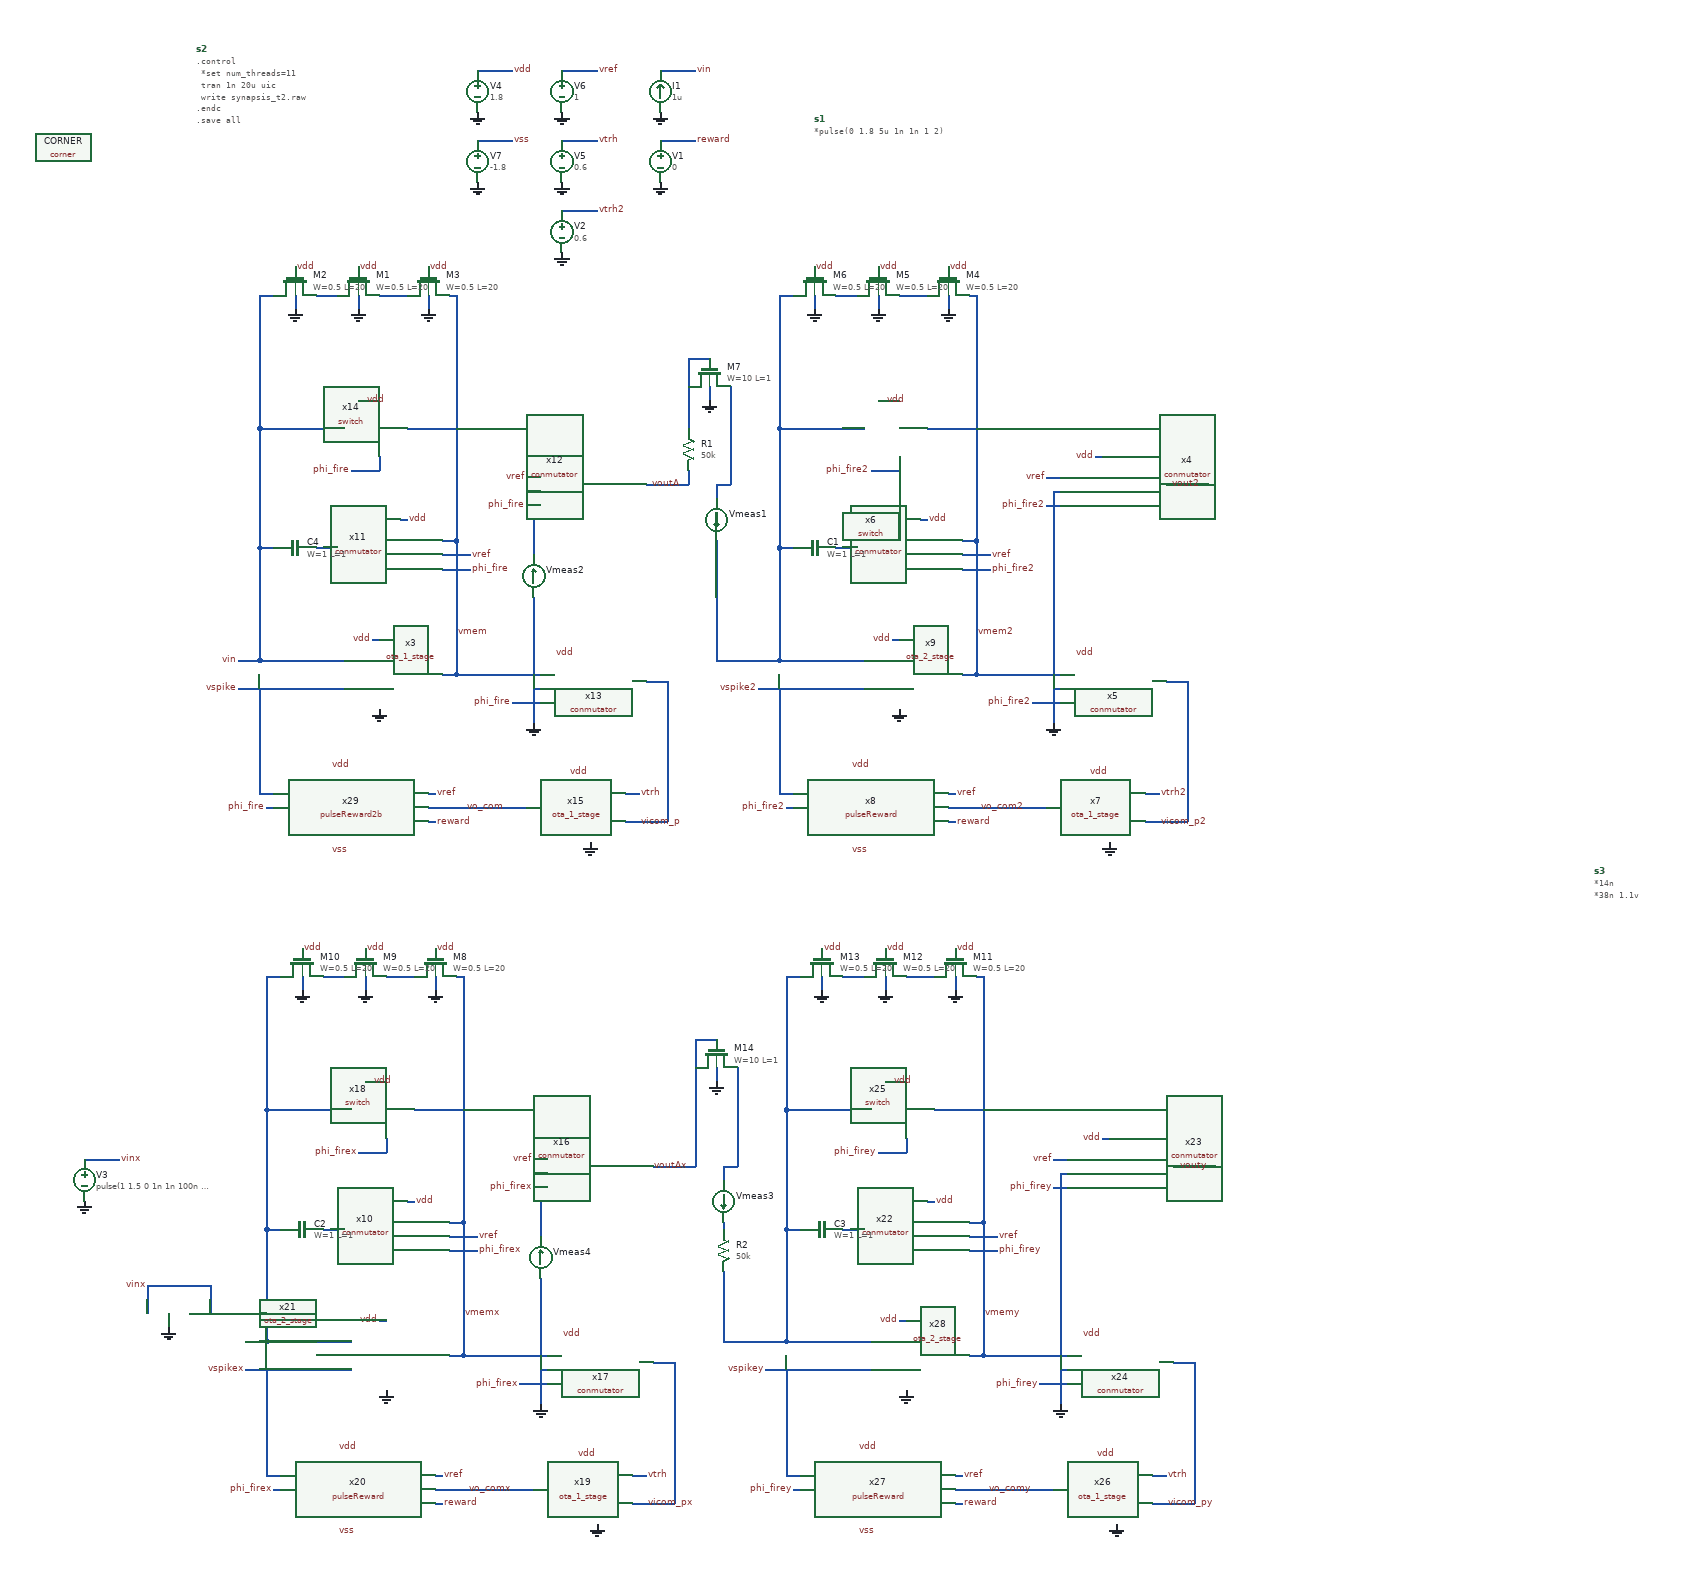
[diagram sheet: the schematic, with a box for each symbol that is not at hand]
v {xschem version=3.4.7 file_version=1.2}
G {}
K {}
V {}
S {}
E {}
B 2 1620 -1070 2420 -670 {flags=graph
y1=0.55
y2=1.3
ypos1=0
ypos2=2
divy=5
subdivy=1
unity=1
x1=9.6886622e-06
x2=1.1063051e-05
divx=5
subdivx=1
xlabmag=1.0
ylabmag=1.0
node="vmem
vtrh"
color="5 9"
dataset=-1
unitx=1
logx=0
logy=0
}
B 2 1620 -670 2420 -270 {flags=graph
y1=0.58
y2=1.7
ypos1=0
ypos2=2
divy=5
subdivy=1
unity=1
x1=9.6886622e-06
x2=1.1063051e-05
divx=5
subdivx=1
xlabmag=1.0
ylabmag=1.0
node="vmem2
vtrh"
color="7 9"
dataset=-1
unitx=1
logx=0
logy=0
}
B 2 2420 -1070 3220 -670 {flags=graph
y1=0.82
y2=1.3
ypos1=0
ypos2=2
divy=5
subdivy=1
unity=1
x1=9.6886622e-06
x2=1.1063051e-05
divx=5
subdivx=1
xlabmag=1.0
ylabmag=1.0
node=vouta
color=4
dataset=-1
unitx=1
logx=0
logy=0
}
B 2 2420 -670 3220 -270 {flags=graph
y1=0.58
y2=1.7
ypos1=0
ypos2=2
divy=5
subdivy=1
unity=1
x1=9.6886622e-06
x2=1.1063051e-05
divx=5
subdivx=1
xlabmag=1.0
ylabmag=1.0
node=vout2
color=4
dataset=-1
unitx=1
logx=0
logy=0
}
B 2 1890 -1530 2690 -1130 {flags=graph
y1=-10e-06
y2=10e-6
ypos1=0
ypos2=2
divy=5
subdivy=1
unity=1
x1=9.6886622e-06
x2=1.1063051e-05
divx=5
subdivx=1
xlabmag=1.0
ylabmag=1.0
node="I(Vmeas1)
I(Vmeas2)"
color="4 5"
dataset=-1
unitx=1
logx=0
logy=0
}
B 2 2690 -1530 3490 -1130 {flags=graph
y1=-1.8e-05
y2=1.1e-05
ypos1=0
ypos2=2
divy=5
subdivy=1
unity=1
x1=9.6886622e-06
x2=1.1063051e-05
divx=5
subdivx=1
xlabmag=1.0
ylabmag=1.0
node="I(Vmeas1)
I(Vmeas2)"
color=4
dataset=-1
unitx=1
logx=0
logy=0
}
B 2 1660 -40 2460 360 {flags=graph
y1=-0.04
y2=1.8
ypos1=0
ypos2=2
divy=5
subdivy=1
unity=1
x1=9.6886622e-06
x2=1.1063051e-05
divx=5
subdivx=1
xlabmag=1.0
ylabmag=1.0
node="vmemx
vtrh"
color="5 9"
dataset=-1
unitx=1
logx=0
logy=0
}
B 2 1660 360 2460 760 {flags=graph
y1=0.59
y2=1.7
ypos1=0
ypos2=2
divy=5
subdivy=1
unity=1
x1=9.6886622e-06
x2=1.1063051e-05
divx=5
subdivx=1
xlabmag=1.0
ylabmag=1.0
node="vmemy
vtrh"
color="7 9"
dataset=-1
unitx=1
logx=0
logy=0
}
B 2 2460 -40 3260 360 {flags=graph
y1=0.024
y2=1.8
ypos1=0
ypos2=2
divy=5
subdivy=1
unity=1
x1=9.6886622e-06
x2=1.1063051e-05
divx=5
subdivx=1
xlabmag=1.0
ylabmag=1.0
node="voutAx
vinx"
color="4 8"
dataset=-1
unitx=1
logx=0
logy=0
}
B 2 2460 360 3260 760 {flags=graph
y1=0.59
y2=1.7
ypos1=0
ypos2=2
divy=5
subdivy=1
unity=1
x1=9.6886622e-06
x2=1.1063051e-05
divx=5
subdivx=1
xlabmag=1.0
ylabmag=1.0
node=vouty
color=4
dataset=-1
unitx=1
logx=0
logy=0
}
N 460 -1340 510 -1340 {
lab=vdd}
N 720 -1340 770 -1340 {
lab=vin}
N 580 -1240 630 -1240 {
lab=vtrh}
N 580 -1340 630 -1340 {
lab=vref}
N 460 -1240 510 -1240 {
lab=vss}
N 720 -1240 770 -1240 {
lab=reward}
N 500 -290 530 -290 {
lab=vo_com}
N 530 -720 550 -720 {
lab=phi_fire}
N 530 -760 550 -760 {
lab=vref}
N 700 -750 720 -750 {
lab=voutA}
N 310 -530 320 -530 {
lab=vdd}
N 350 -700 360 -700 {
lab=vdd}
N 410 -650 450 -650 {
lab=vref}
N 410 -670 430 -670 {
lab=vmem}
N 410 -630 450 -630 {
lab=phi_fire}
N 230 -660 260 -660 {
lab=#net1}
N 430 -940 430 -670 {
lab=vmem}
N 150 -830 150 -660 {
lab=vin}
N 150 -660 170 -660 {
lab=vin}
N 150 -940 150 -830 {
lab=vin}
N 320 -790 320 -770 {
lab=phi_fire}
N 280 -770 320 -770 {
lab=phi_fire}
N 430 -670 430 -480 {
lab=vmem}
N 150 -660 150 -500 {
lab=vin}
N 150 -500 270 -500 {
lab=vin}
N 120 -500 150 -500 {
lab=vin}
N 530 -440 550 -440 {
lab=phi_fire}
N 360 -830 430 -830 {
lab=vmem}
N 150 -830 270 -830 {
lab=vin}
N 290 -870 300 -870 {
lab=vdd}
N 720 -750 760 -750 {
lab=voutA}
N 410 -480 430 -480 {
lab=vmem}
N 600 -790 610 -790 {
lab=vdd}
N 120 -460 270 -460 {
lab=vspike}
N 150 -460 150 -360 {
lab=vspike}
N 390 -290 500 -290 {
lab=vo_com}
N 390 -310 400 -310 {
lab=vref}
N 160 -290 170 -290 {
lab=phi_fire}
N 150 -980 150 -940 {
lab=vin}
N 430 -980 430 -940 {
lab=vmem}
N 390 -270 400 -270 {
lab=reward}
N 150 -310 170 -310 {
lab=vspike}
N 150 -360 150 -310 {
lab=vspike}
N 540 -740 550 -740 {
lab=#net2}
N 670 -310 690 -310 {
lab=vtrh}
N 700 -470 720 -470 {
lab=vicom_p}
N 730 -470 730 -270 {
lab=vicom_p}
N 720 -470 730 -470 {
lab=vicom_p}
N 670 -270 730 -270 {
lab=vicom_p}
N 430 -480 550 -480 {
lab=vmem}
N 510 -440 530 -440 {
lab=phi_fire}
N 540 -460 540 -410 {
lab=GND}
N 540 -460 550 -460 {
lab=GND}
N 390 -1020 390 -1000 {
lab=GND}
N 150 -1020 150 -980 {
lab=vin}
N 430 -1020 430 -980 {
lab=vmem}
N 290 -1020 290 -1000 {
lab=GND}
N 200 -1020 200 -1000 {
lab=GND}
N 150 -1020 170 -1020 {lab=vin}
N 230 -1020 260 -1020 {lab=#net3}
N 320 -1020 360 -1020 {lab=#net4}
N 420 -1020 430 -1020 {lab=vmem}
N 1240 -290 1270 -290 {
lab=vo_com2}
N 1270 -720 1290 -720 {
lab=phi_fire2}
N 1270 -760 1290 -760 {
lab=vref}
N 1440 -750 1460 -750 {
lab=vout2}
N 1050 -530 1060 -530 {
lab=vdd}
N 1090 -700 1100 -700 {
lab=vdd}
N 1150 -650 1190 -650 {
lab=vref}
N 1150 -670 1170 -670 {
lab=vmem2}
N 1150 -630 1190 -630 {
lab=phi_fire2}
N 970 -660 1000 -660 {
lab=#net5}
N 1170 -940 1170 -670 {
lab=vmem2}
N 890 -830 890 -660 {
lab=#net6}
N 890 -660 910 -660 {
lab=#net6}
N 890 -940 890 -830 {
lab=#net6}
N 1060 -790 1060 -770 {
lab=phi_fire2}
N 1020 -770 1060 -770 {
lab=phi_fire2}
N 1170 -670 1170 -480 {
lab=vmem2}
N 890 -660 890 -500 {
lab=#net6}
N 890 -500 1010 -500 {
lab=#net6}
N 860 -500 890 -500 {
lab=#net6}
N 1270 -440 1290 -440 {
lab=phi_fire2}
N 1100 -830 1170 -830 {
lab=vmem2}
N 890 -830 1010 -830 {
lab=#net6}
N 1030 -870 1040 -870 {
lab=vdd}
N 1460 -750 1500 -750 {
lab=vout2}
N 1150 -480 1170 -480 {
lab=vmem2}
N 1340 -790 1350 -790 {
lab=vdd}
N 860 -460 1010 -460 {
lab=vspike2}
N 890 -460 890 -360 {
lab=vspike2}
N 1130 -290 1240 -290 {
lab=vo_com2}
N 1130 -310 1140 -310 {
lab=vref}
N 900 -290 910 -290 {
lab=phi_fire2}
N 890 -980 890 -940 {
lab=#net6}
N 1170 -980 1170 -940 {
lab=vmem2}
N 1130 -270 1140 -270 {
lab=reward}
N 890 -310 910 -310 {
lab=vspike2}
N 890 -360 890 -310 {
lab=vspike2}
N 1280 -740 1290 -740 {
lab=vmem2}
N 1280 -740 1280 -480 {
lab=vmem2}
N 1410 -310 1430 -310 {
lab=vtrh2}
N 1440 -470 1460 -470 {
lab=vicom_p2}
N 1470 -470 1470 -270 {
lab=vicom_p2}
N 1460 -470 1470 -470 {
lab=vicom_p2}
N 1410 -270 1470 -270 {
lab=vicom_p2}
N 1170 -480 1290 -480 {
lab=vmem2}
N 1250 -440 1270 -440 {
lab=phi_fire2}
N 1280 -460 1280 -410 {
lab=GND}
N 1280 -460 1290 -460 {
lab=GND}
N 1130 -1020 1130 -1000 {
lab=GND}
N 890 -1020 890 -980 {
lab=#net6}
N 1170 -1020 1170 -980 {
lab=vmem2}
N 1030 -1020 1030 -1000 {
lab=GND}
N 940 -1020 940 -1000 {
lab=GND}
N 890 -1020 910 -1020 {lab=#net6}
N 970 -1020 1000 -1020 {lab=#net7}
N 1060 -1020 1100 -1020 {lab=#net8}
N 1160 -1020 1170 -1020 {lab=vmem2}
N 800 -500 860 -500 {lab=#net6}
N 580 -1140 630 -1140 {
lab=vtrh2}
N 800 -600 800 -500 {lab=#net6}
N 800 -670 800 -660 {lab=#net6}
N 800 -750 800 -730 {lab=#net9}
N 760 -770 760 -750 {lab=voutA}
N 530 -740 540 -740 {lab=#net2}
N 540 -740 540 -650 {lab=#net2}
N 540 -590 540 -480 {lab=vmem}
N 760 -930 760 -890 {lab=#net10}
N 760 -930 790 -930 {lab=#net10}
N 790 -890 790 -870 {lab=GND}
N 820 -890 820 -750 {lab=#net9}
N 800 -750 820 -750 {lab=#net9}
N 510 680 540 680 {
lab=vo_comx}
N 540 250 560 250 {
lab=phi_firex}
N 540 210 560 210 {
lab=vref}
N 710 220 730 220 {
lab=voutAx}
N 320 440 330 440 {
lab=vdd}
N 360 270 370 270 {
lab=vdd}
N 420 320 460 320 {
lab=vref}
N 420 300 440 300 {
lab=vmemx}
N 420 340 460 340 {
lab=phi_firex}
N 240 310 270 310 {
lab=#net11}
N 440 30 440 300 {
lab=vmemx}
N 160 140 160 310 {
lab=vinx}
N 160 310 180 310 {
lab=vinx}
N 160 30 160 140 {
lab=vinx}
N 330 180 330 200 {
lab=phi_firex}
N 290 200 330 200 {
lab=phi_firex}
N 440 300 440 490 {
lab=vmemx}
N 160 310 160 470 {
lab=vinx}
N 160 470 280 470 {
lab=vinx}
N 130 470 160 470 {
lab=vinx}
N 540 530 560 530 {
lab=phi_firex}
N 370 140 440 140 {
lab=vmemx}
N 160 140 280 140 {
lab=vinx}
N 300 100 310 100 {
lab=vdd}
N 730 220 770 220 {
lab=voutAx}
N 420 490 440 490 {
lab=vmemx}
N 610 180 620 180 {
lab=vdd}
N 130 510 280 510 {
lab=vspikex}
N 160 510 160 610 {
lab=vspikex}
N 400 680 510 680 {
lab=vo_comx}
N 400 660 410 660 {
lab=vref}
N 170 680 180 680 {
lab=phi_firex}
N 160 -10 160 30 {
lab=vinx}
N 440 -10 440 30 {
lab=vmemx}
N 400 700 410 700 {
lab=reward}
N 160 660 180 660 {
lab=vspikex}
N 160 610 160 660 {
lab=vspikex}
N 550 230 560 230 {
lab=#net12}
N 680 660 700 660 {
lab=vtrh}
N 710 500 730 500 {
lab=vicom_px}
N 740 500 740 700 {
lab=vicom_px}
N 730 500 740 500 {
lab=vicom_px}
N 680 700 740 700 {
lab=vicom_px}
N 440 490 560 490 {
lab=vmemx}
N 520 530 540 530 {
lab=phi_firex}
N 550 510 550 560 {
lab=GND}
N 550 510 560 510 {
lab=GND}
N 400 -50 400 -30 {
lab=GND}
N 160 -50 160 -10 {
lab=vinx}
N 440 -50 440 -10 {
lab=vmemx}
N 300 -50 300 -30 {
lab=GND}
N 210 -50 210 -30 {
lab=GND}
N 160 -50 180 -50 {lab=vinx}
N 240 -50 270 -50 {lab=#net13}
N 330 -50 370 -50 {lab=#net14}
N 430 -50 440 -50 {lab=vmemx}
N 1250 680 1280 680 {
lab=vo_comy}
N 1280 250 1300 250 {
lab=phi_firey}
N 1280 210 1300 210 {
lab=vref}
N 1450 220 1470 220 {
lab=vouty}
N 1060 440 1070 440 {
lab=vdd}
N 1100 270 1110 270 {
lab=vdd}
N 1160 320 1200 320 {
lab=vref}
N 1160 300 1180 300 {
lab=vmemy}
N 1160 340 1200 340 {
lab=phi_firey}
N 980 310 1010 310 {
lab=#net15}
N 1180 30 1180 300 {
lab=vmemy}
N 900 140 900 310 {
lab=#net16}
N 900 310 920 310 {
lab=#net16}
N 900 30 900 140 {
lab=#net16}
N 1070 180 1070 200 {
lab=phi_firey}
N 1030 200 1070 200 {
lab=phi_firey}
N 1180 300 1180 490 {
lab=vmemy}
N 900 310 900 470 {
lab=#net16}
N 900 470 1020 470 {
lab=#net16}
N 870 470 900 470 {
lab=#net16}
N 1280 530 1300 530 {
lab=phi_firey}
N 1110 140 1180 140 {
lab=vmemy}
N 900 140 1020 140 {
lab=#net16}
N 1040 100 1050 100 {
lab=vdd}
N 1470 220 1510 220 {
lab=vouty}
N 1160 490 1180 490 {
lab=vmemy}
N 1350 180 1360 180 {
lab=vdd}
N 870 510 1020 510 {
lab=vspikey}
N 900 510 900 610 {
lab=vspikey}
N 1140 680 1250 680 {
lab=vo_comy}
N 1140 660 1150 660 {
lab=vref}
N 910 680 920 680 {
lab=phi_firey}
N 900 -10 900 30 {
lab=#net16}
N 1180 -10 1180 30 {
lab=vmemy}
N 1140 700 1150 700 {
lab=reward}
N 900 660 920 660 {
lab=vspikey}
N 900 610 900 660 {
lab=vspikey}
N 1290 230 1300 230 {
lab=vmemy}
N 1290 230 1290 490 {
lab=vmemy}
N 1420 660 1440 660 {
lab=vtrh}
N 1450 500 1470 500 {
lab=vicom_py}
N 1480 500 1480 700 {
lab=vicom_py}
N 1470 500 1480 500 {
lab=vicom_py}
N 1420 700 1480 700 {
lab=vicom_py}
N 1180 490 1300 490 {
lab=vmemy}
N 1260 530 1280 530 {
lab=phi_firey}
N 1290 510 1290 560 {
lab=GND}
N 1290 510 1300 510 {
lab=GND}
N 1140 -50 1140 -30 {
lab=GND}
N 900 -50 900 -10 {
lab=#net16}
N 1180 -50 1180 -10 {
lab=vmemy}
N 1040 -50 1040 -30 {
lab=GND}
N 950 -50 950 -30 {
lab=GND}
N 900 -50 920 -50 {lab=#net16}
N 980 -50 1010 -50 {lab=#net17}
N 1070 -50 1110 -50 {lab=#net18}
N 1170 -50 1180 -50 {lab=vmemy}
N 810 470 870 470 {lab=#net16}
N 810 370 810 470 {lab=#net16}
N 810 300 810 310 {lab=#net19}
N 810 220 810 240 {lab=#net20}
N 770 200 770 220 {lab=voutAx}
N 540 230 550 230 {lab=#net12}
N 550 230 550 320 {lab=#net12}
N 550 380 550 490 {lab=vmemx}
N 770 40 770 80 {lab=voutAx}
N 770 40 800 40 {lab=voutAx}
N 800 80 800 100 {lab=GND}
N 770 80 770 200 {lab=voutAx}
N 830 80 830 220 {lab=#net20}
N 810 220 830 220 {lab=#net20}
N -100 210 -50 210 {
lab=vinx}
N -10 390 -10 430 {lab=vinx}
N -10 390 20 390 {lab=vinx}
N 20 430 20 450 {lab=GND}
N 50 430 160 430 {lab=vinx}
N 760 -890 760 -830 {lab=#net10}
N 800 -660 800 -590 {lab=#net6}
N 20 390 80 390 {lab=vinx}
N 80 390 80 430 {lab=vinx}
C {devices/code_shown.sym} 60 -1370 0 0 {name=s2 only_toplevel=false value="
.control
 *set num_threads=11
 tran 1n 20u uic
 write synapsis_t2.raw
.endc
.save all" }
C {devices/gnd.sym} 720 -1280 0 0 {name=l8 lab=GND}
C {devices/vsource.sym} 460 -1310 0 0 {name=V4 value=1.8}
C {devices/gnd.sym} 460 -1280 0 0 {name=l9 lab=GND}
C {devices/lab_wire.sym} 510 -1340 0 1 {name=p61 sig_type=std_logic lab=vdd}
C {devices/lab_wire.sym} 770 -1340 0 1 {name=p62 sig_type=std_logic lab=vin}
C {devices/vsource.sym} 580 -1210 0 0 {name=V5 value=0.6}
C {devices/gnd.sym} 580 -1180 0 0 {name=l10 lab=GND}
C {devices/lab_wire.sym} 630 -1240 0 1 {name=p63 sig_type=std_logic lab=vtrh}
C {devices/vsource.sym} 580 -1310 0 0 {name=V6 value=1}
C {devices/gnd.sym} 580 -1280 0 0 {name=l11 lab=GND}
C {devices/lab_wire.sym} 630 -1340 0 1 {name=p64 sig_type=std_logic lab=vref}
C {devices/isource.sym} 720 -1310 2 1 {name=I1 value=1u}
C {devices/vsource.sym} 460 -1210 0 0 {name=V7 value=-1.8}
C {devices/gnd.sym} 460 -1180 0 0 {name=l13 lab=GND}
C {devices/lab_wire.sym} 510 -1240 0 1 {name=p72 sig_type=std_logic lab=vss}
C {devices/vsource.sym} 720 -1210 0 0 {name=V1 value=0}
C {devices/gnd.sym} 720 -1180 0 0 {name=l2 lab=GND}
C {devices/lab_wire.sym} 770 -1240 0 1 {name=p5 sig_type=std_logic lab=reward}
C {devices/lab_wire.sym} 250 -350 0 1 {name=p48 sig_type=std_logic lab=vdd}
C {devices/lab_wire.sym} 500 -290 0 0 {name=p49 sig_type=std_logic lab=vo_com}
C {devices/lab_wire.sym} 690 -310 0 1 {name=p50 sig_type=std_logic lab=vtrh}
C {devices/lab_wire.sym} 620 -340 0 0 {name=p51 sig_type=std_logic lab=vdd}
C {devices/lab_wire.sym} 120 -460 0 0 {name=p52 sig_type=std_logic lab=vspike}
C {devices/lab_wire.sym} 530 -720 0 0 {name=p53 sig_type=std_logic lab=phi_fire}
C {devices/lab_wire.sym} 530 -760 0 0 {name=p54 sig_type=std_logic lab=vref}
C {devices/lab_wire.sym} 310 -530 0 0 {name=p55 sig_type=std_logic lab=vdd}
C {devices/lab_wire.sym} 600 -790 0 0 {name=p56 sig_type=std_logic lab=vdd}
C {devices/lab_wire.sym} 360 -700 0 1 {name=p57 sig_type=std_logic lab=vdd}
C {devices/lab_wire.sym} 450 -630 0 1 {name=p58 sig_type=std_logic lab=phi_fire}
C {devices/lab_wire.sym} 280 -770 0 0 {name=p59 sig_type=std_logic lab=phi_fire}
C {devices/lab_wire.sym} 430 -540 0 1 {name=p60 sig_type=std_logic lab=vmem}
C {devices/lab_wire.sym} 120 -500 0 0 {name=p65 sig_type=std_logic lab=vin}
C {devices/lab_wire.sym} 690 -270 2 0 {name=p66 sig_type=std_logic lab=vicom_p}
C {/foss/designs/spike_130/designs/subcells/core_conmutator/conmutator.sym} 410 -600 0 1 {name=x11}
C {/foss/designs/spike_130/designs/subcells/core_conmutator/conmutator.sym} 550 -690 0 0 {name=x12}
C {devices/lab_wire.sym} 510 -440 0 0 {name=p67 sig_type=std_logic lab=phi_fire}
C {devices/lab_wire.sym} 600 -510 0 0 {name=p68 sig_type=std_logic lab=vdd}
C {/foss/designs/spike_130/designs/subcells/core_conmutator/conmutator.sym} 550 -410 0 0 {name=x13}
C {devices/gnd.sym} 540 -410 0 0 {name=l12 lab=GND}
C {/foss/designs/spike_130/designs/subcells/core_switch/switch.sym} 250 -770 0 0 {name=x14}
C {devices/lab_wire.sym} 300 -870 0 1 {name=p69 sig_type=std_logic lab=vdd}
C {devices/lab_wire.sym} 750 -750 0 0 {name=p70 sig_type=std_logic lab=voutA}
C {devices/lab_wire.sym} 450 -650 0 1 {name=p71 sig_type=std_logic lab=vref}
C {/foss/designs/spike_130/designs/subcells/core_ota_1stage/ota_1_stage.sym} 620 -290 0 1 {name=x15}
C {devices/gnd.sym} 620 -240 0 1 {name=l14 lab=GND}
C {devices/lab_wire.sym} 400 -310 0 1 {name=p1 sig_type=std_logic lab=vref}
C {devices/lab_wire.sym} 160 -290 2 1 {name=p2 sig_type=std_logic lab=phi_fire}
C {sky130_fd_pr/cap_mim_m3_2.sym} 200 -660 3 0 {name=C4 model=cap_mim_m3_2 W=1 L=1 MF=200 spiceprefix=X}
C {devices/lab_wire.sym} 250 -230 0 1 {name=p3 sig_type=std_logic lab=vss}
C {devices/gnd.sym} 320 -430 0 1 {name=l1 lab=GND}
C {devices/lab_wire.sym} 400 -270 0 1 {name=p6 sig_type=std_logic lab=reward}
C {sky130_fd_pr/corner.sym} -130 -1230 0 0 {name=CORNER only_toplevel=true corner=tt}
C {sky130_fd_pr/nfet_01v8.sym} 390 -1040 1 0 {name=M3
L=20
W=0.5
nf=1 mult=1
model=nfet_01v8
spiceprefix=X
}
C {devices/gnd.sym} 390 -1000 0 0 {name=l17 lab=GND}
C {devices/lab_wire.sym} 390 -1060 0 1 {name=p4 sig_type=std_logic lab=vdd}
C {sky130_fd_pr/nfet_01v8.sym} 290 -1040 1 0 {name=M1
L=20
W=0.5
nf=1 mult=1
model=nfet_01v8
spiceprefix=X
}
C {devices/gnd.sym} 290 -1000 0 0 {name=l3 lab=GND}
C {devices/lab_wire.sym} 290 -1060 0 1 {name=p14 sig_type=std_logic lab=vdd}
C {sky130_fd_pr/nfet_01v8.sym} 200 -1040 1 0 {name=M2
L=20
W=0.5
nf=1 mult=1
model=nfet_01v8
spiceprefix=X
}
C {devices/gnd.sym} 200 -1000 0 0 {name=l4 lab=GND}
C {devices/lab_wire.sym} 200 -1060 0 1 {name=p15 sig_type=std_logic lab=vdd}
C {devices/lab_wire.sym} 990 -350 0 1 {name=p7 sig_type=std_logic lab=vdd}
C {devices/lab_wire.sym} 1240 -290 0 0 {name=p8 sig_type=std_logic lab=vo_com2}
C {devices/lab_wire.sym} 1430 -310 0 1 {name=p9 sig_type=std_logic lab=vtrh2}
C {devices/lab_wire.sym} 1360 -340 0 0 {name=p10 sig_type=std_logic lab=vdd}
C {devices/lab_wire.sym} 860 -460 0 0 {name=p11 sig_type=std_logic lab=vspike2}
C {devices/lab_wire.sym} 1270 -720 0 0 {name=p12 sig_type=std_logic lab=phi_fire2}
C {devices/lab_wire.sym} 1270 -760 0 0 {name=p13 sig_type=std_logic lab=vref}
C {devices/lab_wire.sym} 1050 -530 0 0 {name=p16 sig_type=std_logic lab=vdd}
C {devices/lab_wire.sym} 1340 -790 0 0 {name=p17 sig_type=std_logic lab=vdd}
C {devices/lab_wire.sym} 1100 -700 0 1 {name=p18 sig_type=std_logic lab=vdd}
C {devices/lab_wire.sym} 1190 -630 0 1 {name=p19 sig_type=std_logic lab=phi_fire2}
C {devices/lab_wire.sym} 1020 -770 0 0 {name=p20 sig_type=std_logic lab=phi_fire2}
C {devices/lab_wire.sym} 1170 -540 0 1 {name=p21 sig_type=std_logic lab=vmem2}
C {devices/lab_wire.sym} 1430 -270 2 0 {name=p23 sig_type=std_logic lab=vicom_p2}
C {/foss/designs/spike_130/designs/subcells/core_conmutator/conmutator.sym} 1150 -600 0 1 {name=x2}
C {/foss/designs/spike_130/designs/subcells/core_conmutator/conmutator.sym} 1290 -690 0 0 {name=x4}
C {devices/lab_wire.sym} 1250 -440 0 0 {name=p24 sig_type=std_logic lab=phi_fire2}
C {devices/lab_wire.sym} 1340 -510 0 0 {name=p25 sig_type=std_logic lab=vdd}
C {/foss/designs/spike_130/designs/subcells/core_conmutator/conmutator.sym} 1290 -410 0 0 {name=x5}
C {devices/gnd.sym} 1280 -410 0 0 {name=l5 lab=GND}
C {/foss/designs/spike_130/designs/subcells/core_switch/switch.sym} 990 -770 0 0 {name=x6}
C {devices/lab_wire.sym} 1040 -870 0 1 {name=p26 sig_type=std_logic lab=vdd}
C {devices/lab_wire.sym} 1490 -750 0 0 {name=p27 sig_type=std_logic lab=vout2}
C {devices/lab_wire.sym} 1190 -650 0 1 {name=p28 sig_type=std_logic lab=vref}
C {/foss/designs/spike_130/designs/subcells/core_ota_1stage/ota_1_stage.sym} 1360 -290 0 1 {name=x7}
C {devices/gnd.sym} 1360 -240 0 1 {name=l6 lab=GND}
C {devices/lab_wire.sym} 1140 -310 0 1 {name=p29 sig_type=std_logic lab=vref}
C {devices/lab_wire.sym} 900 -290 2 1 {name=p30 sig_type=std_logic lab=phi_fire2}
C {devices/lab_wire.sym} 990 -230 0 1 {name=p31 sig_type=std_logic lab=vss}
C {devices/gnd.sym} 1060 -430 0 1 {name=l7 lab=GND}
C {/foss/designs/spike_130/designs/subcells/core_pulseReward/pulseReward.sym} 1020 -300 0 1 {name=x8}
C {devices/lab_wire.sym} 1140 -270 0 1 {name=p32 sig_type=std_logic lab=reward}
C {/foss/designs/spike_130/designs/subcells/core_ota_2stage/ota_2_stage.sym} 1060 -480 0 0 {name=x9}
C {sky130_fd_pr/nfet_01v8.sym} 1130 -1040 1 0 {name=M4
L=20
W=0.5
nf=1 mult=1
model=nfet_01v8
spiceprefix=X
}
C {devices/gnd.sym} 1130 -1000 0 0 {name=l15 lab=GND}
C {devices/lab_wire.sym} 1130 -1060 0 1 {name=p33 sig_type=std_logic lab=vdd}
C {sky130_fd_pr/nfet_01v8.sym} 1030 -1040 1 0 {name=M5
L=20
W=0.5
nf=1 mult=1
model=nfet_01v8
spiceprefix=X
}
C {devices/gnd.sym} 1030 -1000 0 0 {name=l16 lab=GND}
C {devices/lab_wire.sym} 1030 -1060 0 1 {name=p34 sig_type=std_logic lab=vdd}
C {sky130_fd_pr/nfet_01v8.sym} 940 -1040 1 0 {name=M6
L=20
W=0.5
nf=1 mult=1
model=nfet_01v8
spiceprefix=X
}
C {devices/gnd.sym} 940 -1000 0 0 {name=l18 lab=GND}
C {devices/lab_wire.sym} 940 -1060 0 1 {name=p35 sig_type=std_logic lab=vdd}
C {devices/vsource.sym} 580 -1110 0 0 {name=V2 value=0.6}
C {devices/gnd.sym} 580 -1080 0 0 {name=l19 lab=GND}
C {devices/lab_wire.sym} 630 -1140 0 1 {name=p22 sig_type=std_logic lab=vtrh2}
C {launcher.sym} 1480 -940 0 0 {name=h5
descr="load waves" 
tclcommand="xschem raw_read $netlist_dir/synapsis_t2.raw tran"
}
C {devices/code_shown.sym} 940 -1270 0 0 {name=s1 only_toplevel=false value="*pulse(0 1.8 5u 1n 1n 1 2)" }
C {devices/code_shown.sym} 2050 -200 0 0 {name=s3 only_toplevel=false value="*14n
*38n 1.1v" }
C {res.sym} 760 -800 0 0 {name=R1
value=50k
footprint=1206
device=resistor
m=1}
C {devices/ammeter.sym} 800 -700 0 0 {name=Vmeas1 savecurrent=true spice_ignore=0}
C {devices/ammeter.sym} 540 -620 2 0 {name=Vmeas2 savecurrent=true spice_ignore=0}
C {sky130_fd_pr/nfet_01v8.sym} 790 -910 3 1 {name=M7
L=1
W=10
nf=1 mult=1
model=nfet_01v8
spiceprefix=X
}
C {devices/gnd.sym} 790 -870 0 1 {name=l20 lab=GND}
C {sky130_fd_pr/cap_mim_m3_2.sym} 940 -660 3 0 {name=C1 model=cap_mim_m3_2 W=1 L=1 MF=20 spiceprefix=X}
C {devices/lab_wire.sym} 260 620 0 1 {name=p36 sig_type=std_logic lab=vdd}
C {devices/lab_wire.sym} 510 680 0 0 {name=p37 sig_type=std_logic lab=vo_comx}
C {devices/lab_wire.sym} 700 660 0 1 {name=p38 sig_type=std_logic lab=vtrh}
C {devices/lab_wire.sym} 630 630 0 0 {name=p39 sig_type=std_logic lab=vdd}
C {devices/lab_wire.sym} 130 510 0 0 {name=p40 sig_type=std_logic lab=vspikex}
C {devices/lab_wire.sym} 540 250 0 0 {name=p41 sig_type=std_logic lab=phi_firex}
C {devices/lab_wire.sym} 540 210 0 0 {name=p42 sig_type=std_logic lab=vref}
C {devices/lab_wire.sym} 320 440 0 0 {name=p43 sig_type=std_logic lab=vdd}
C {devices/lab_wire.sym} 610 180 0 0 {name=p44 sig_type=std_logic lab=vdd}
C {devices/lab_wire.sym} 370 270 0 1 {name=p45 sig_type=std_logic lab=vdd}
C {devices/lab_wire.sym} 460 340 0 1 {name=p46 sig_type=std_logic lab=phi_firex}
C {devices/lab_wire.sym} 290 200 0 0 {name=p47 sig_type=std_logic lab=phi_firex}
C {devices/lab_wire.sym} 440 430 0 1 {name=p73 sig_type=std_logic lab=vmemx}
C {devices/lab_wire.sym} 700 700 2 0 {name=p75 sig_type=std_logic lab=vicom_px}
C {/foss/designs/spike_130/designs/subcells/core_conmutator/conmutator.sym} 420 370 0 1 {name=x10}
C {/foss/designs/spike_130/designs/subcells/core_conmutator/conmutator.sym} 560 280 0 0 {name=x16}
C {devices/lab_wire.sym} 520 530 0 0 {name=p76 sig_type=std_logic lab=phi_firex}
C {devices/lab_wire.sym} 610 460 0 0 {name=p77 sig_type=std_logic lab=vdd}
C {/foss/designs/spike_130/designs/subcells/core_conmutator/conmutator.sym} 560 560 0 0 {name=x17}
C {devices/gnd.sym} 550 560 0 0 {name=l21 lab=GND}
C {/foss/designs/spike_130/designs/subcells/core_switch/switch.sym} 260 200 0 0 {name=x18}
C {devices/lab_wire.sym} 310 100 0 1 {name=p78 sig_type=std_logic lab=vdd}
C {devices/lab_wire.sym} 760 220 0 0 {name=p79 sig_type=std_logic lab=voutAx}
C {devices/lab_wire.sym} 460 320 0 1 {name=p80 sig_type=std_logic lab=vref}
C {/foss/designs/spike_130/designs/subcells/core_ota_1stage/ota_1_stage.sym} 630 680 0 1 {name=x19}
C {devices/gnd.sym} 630 730 0 1 {name=l22 lab=GND}
C {devices/lab_wire.sym} 410 660 0 1 {name=p81 sig_type=std_logic lab=vref}
C {devices/lab_wire.sym} 170 680 2 1 {name=p82 sig_type=std_logic lab=phi_firex}
C {sky130_fd_pr/cap_mim_m3_2.sym} 210 310 3 0 {name=C2 model=cap_mim_m3_2 W=1 L=1 MF=200 spiceprefix=X}
C {devices/lab_wire.sym} 260 740 0 1 {name=p83 sig_type=std_logic lab=vss}
C {devices/gnd.sym} 330 540 0 1 {name=l23 lab=GND}
C {/foss/designs/spike_130/designs/subcells/core_pulseReward/pulseReward.sym} 290 670 0 1 {name=x20}
C {devices/lab_wire.sym} 410 700 0 1 {name=p84 sig_type=std_logic lab=reward}
C {/foss/designs/spike_130/designs/subcells/core_ota_2stage/ota_2_stage.sym} 330 490 0 0 {name=x21}
C {sky130_fd_pr/nfet_01v8.sym} 400 -70 1 0 {name=M8
L=20
W=0.5
nf=1 mult=1
model=nfet_01v8
spiceprefix=X
}
C {devices/gnd.sym} 400 -30 0 0 {name=l24 lab=GND}
C {devices/lab_wire.sym} 400 -90 0 1 {name=p85 sig_type=std_logic lab=vdd}
C {sky130_fd_pr/nfet_01v8.sym} 300 -70 1 0 {name=M9
L=20
W=0.5
nf=1 mult=1
model=nfet_01v8
spiceprefix=X
}
C {devices/gnd.sym} 300 -30 0 0 {name=l25 lab=GND}
C {devices/lab_wire.sym} 300 -90 0 1 {name=p86 sig_type=std_logic lab=vdd}
C {sky130_fd_pr/nfet_01v8.sym} 210 -70 1 0 {name=M10
L=20
W=0.5
nf=1 mult=1
model=nfet_01v8
spiceprefix=X
}
C {devices/gnd.sym} 210 -30 0 0 {name=l26 lab=GND}
C {devices/lab_wire.sym} 210 -90 0 1 {name=p87 sig_type=std_logic lab=vdd}
C {devices/lab_wire.sym} 1000 620 0 1 {name=p88 sig_type=std_logic lab=vdd}
C {devices/lab_wire.sym} 1250 680 0 0 {name=p89 sig_type=std_logic lab=vo_comy}
C {devices/lab_wire.sym} 1440 660 0 1 {name=p90 sig_type=std_logic lab=vtrh}
C {devices/lab_wire.sym} 1370 630 0 0 {name=p91 sig_type=std_logic lab=vdd}
C {devices/lab_wire.sym} 870 510 0 0 {name=p92 sig_type=std_logic lab=vspikey}
C {devices/lab_wire.sym} 1280 250 0 0 {name=p93 sig_type=std_logic lab=phi_firey}
C {devices/lab_wire.sym} 1280 210 0 0 {name=p94 sig_type=std_logic lab=vref}
C {devices/lab_wire.sym} 1060 440 0 0 {name=p95 sig_type=std_logic lab=vdd}
C {devices/lab_wire.sym} 1350 180 0 0 {name=p96 sig_type=std_logic lab=vdd}
C {devices/lab_wire.sym} 1110 270 0 1 {name=p97 sig_type=std_logic lab=vdd}
C {devices/lab_wire.sym} 1200 340 0 1 {name=p98 sig_type=std_logic lab=phi_firey}
C {devices/lab_wire.sym} 1030 200 0 0 {name=p99 sig_type=std_logic lab=phi_firey}
C {devices/lab_wire.sym} 1180 430 0 1 {name=p100 sig_type=std_logic lab=vmemy}
C {devices/lab_wire.sym} 1440 700 2 0 {name=p101 sig_type=std_logic lab=vicom_py}
C {/foss/designs/spike_130/designs/subcells/core_conmutator/conmutator.sym} 1160 370 0 1 {name=x22}
C {/foss/designs/spike_130/designs/subcells/core_conmutator/conmutator.sym} 1300 280 0 0 {name=x23}
C {devices/lab_wire.sym} 1260 530 0 0 {name=p102 sig_type=std_logic lab=phi_firey}
C {devices/lab_wire.sym} 1350 460 0 0 {name=p103 sig_type=std_logic lab=vdd}
C {/foss/designs/spike_130/designs/subcells/core_conmutator/conmutator.sym} 1300 560 0 0 {name=x24}
C {devices/gnd.sym} 1290 560 0 0 {name=l27 lab=GND}
C {/foss/designs/spike_130/designs/subcells/core_switch/switch.sym} 1000 200 0 0 {name=x25}
C {devices/lab_wire.sym} 1050 100 0 1 {name=p104 sig_type=std_logic lab=vdd}
C {devices/lab_wire.sym} 1500 220 0 0 {name=p105 sig_type=std_logic lab=vouty}
C {devices/lab_wire.sym} 1200 320 0 1 {name=p106 sig_type=std_logic lab=vref}
C {/foss/designs/spike_130/designs/subcells/core_ota_1stage/ota_1_stage.sym} 1370 680 0 1 {name=x26}
C {devices/gnd.sym} 1370 730 0 1 {name=l28 lab=GND}
C {devices/lab_wire.sym} 1150 660 0 1 {name=p107 sig_type=std_logic lab=vref}
C {devices/lab_wire.sym} 910 680 2 1 {name=p108 sig_type=std_logic lab=phi_firey}
C {devices/lab_wire.sym} 1000 740 0 1 {name=p109 sig_type=std_logic lab=vss}
C {devices/gnd.sym} 1070 540 0 1 {name=l29 lab=GND}
C {/foss/designs/spike_130/designs/subcells/core_pulseReward/pulseReward.sym} 1030 670 0 1 {name=x27}
C {devices/lab_wire.sym} 1150 700 0 1 {name=p110 sig_type=std_logic lab=reward}
C {/foss/designs/spike_130/designs/subcells/core_ota_2stage/ota_2_stage.sym} 1070 490 0 0 {name=x28}
C {sky130_fd_pr/nfet_01v8.sym} 1140 -70 1 0 {name=M11
L=20
W=0.5
nf=1 mult=1
model=nfet_01v8
spiceprefix=X
}
C {devices/gnd.sym} 1140 -30 0 0 {name=l30 lab=GND}
C {devices/lab_wire.sym} 1140 -90 0 1 {name=p111 sig_type=std_logic lab=vdd}
C {sky130_fd_pr/nfet_01v8.sym} 1040 -70 1 0 {name=M12
L=20
W=0.5
nf=1 mult=1
model=nfet_01v8
spiceprefix=X
}
C {devices/gnd.sym} 1040 -30 0 0 {name=l31 lab=GND}
C {devices/lab_wire.sym} 1040 -90 0 1 {name=p112 sig_type=std_logic lab=vdd}
C {sky130_fd_pr/nfet_01v8.sym} 950 -70 1 0 {name=M13
L=20
W=0.5
nf=1 mult=1
model=nfet_01v8
spiceprefix=X
}
C {devices/gnd.sym} 950 -30 0 0 {name=l32 lab=GND}
C {devices/lab_wire.sym} 950 -90 0 1 {name=p113 sig_type=std_logic lab=vdd}
C {launcher.sym} 1500 30 0 0 {name=h1
descr="load waves" 
tclcommand="xschem raw_read $netlist_dir/synapsis_t2.raw tran"
}
C {res.sym} 810 340 0 0 {name=R2
value=50k
footprint=1206
device=resistor
m=1}
C {devices/ammeter.sym} 810 270 0 0 {name=Vmeas3 savecurrent=true spice_ignore=0}
C {devices/ammeter.sym} 550 350 2 0 {name=Vmeas4 savecurrent=true spice_ignore=0}
C {sky130_fd_pr/nfet_01v8.sym} 800 60 3 1 {name=M14
L=1
W=10
nf=1 mult=1
model=nfet_01v8
spiceprefix=X
}
C {devices/gnd.sym} 800 100 0 1 {name=l34 lab=GND}
C {sky130_fd_pr/cap_mim_m3_2.sym} 950 310 3 0 {name=C3 model=cap_mim_m3_2 W=1 L=1 MF=200 spiceprefix=X}
C {devices/gnd.sym} -100 270 0 0 {name=l33 lab=GND}
C {devices/lab_wire.sym} -50 210 0 1 {name=p114 sig_type=std_logic lab=vinx}
C {devices/vsource.sym} -100 240 0 0 {name=V3 value="pulse(1 1.5 0 1n 1n 100n 250n)"}
C {devices/gnd.sym} 20 450 0 1 {name=l35 lab=GND}
C {devices/lab_wire.sym} -10 390 0 0 {name=p115 sig_type=std_logic lab=vinx}
C {/foss/designs/spike_130/designs/subcells/core_ota_1stage/ota_1_stage.sym} 320 -480 0 0 {name=x3}
C {/foss/designs/spike_130/designs/subcells/core_pulseReward2/pulseReward2b.sym} 280 -290 0 1 {name=x29}
